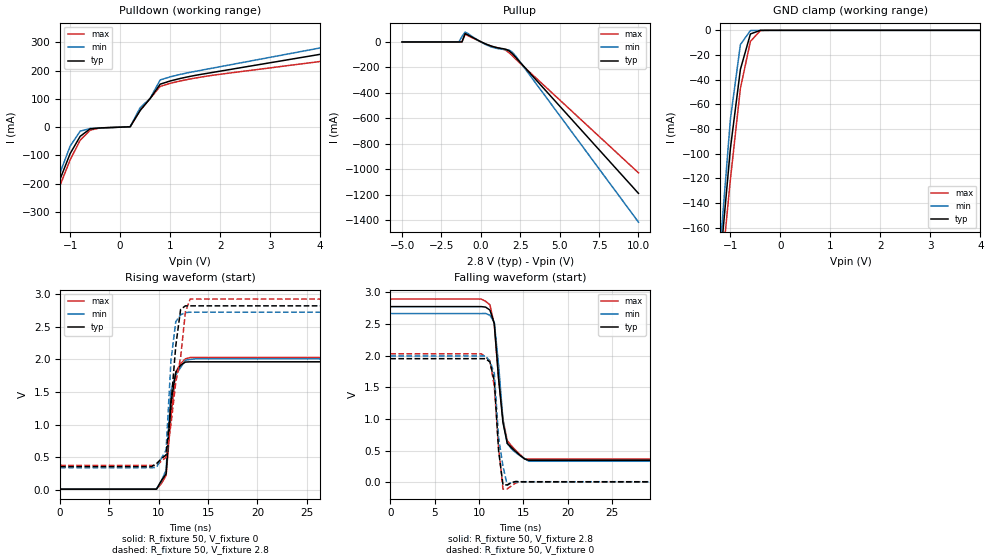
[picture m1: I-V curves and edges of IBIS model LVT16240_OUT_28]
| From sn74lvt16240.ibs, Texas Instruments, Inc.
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|  Model  LVT16240 OUTPUT_28
[Model]   LVT16240_OUT_28
Model_type  3-state
Polarity   Inverting
Enable   Active-Low
Vmeas = 1.5V
Cref = 50pF
Rref = 500
Vref = 0
| variable   typ   min   max
C_comp   9pf   NA   NA
[Temperature Range]   40   -25   100
| Ambient temperature   25   -40   85
[Voltage range]   2.8   2.7   2.9
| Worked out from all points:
|   slope of the pulldown table from 0 to 0.42 V, typ, clamps not added: 6.58 ohm
|   slope of the pullup table from 0 to 0.42 V, typ, clamps not added: 18.2 ohm
|   GND clamp passes 1 mA (typ) near -0.47 V on its own axis
|   rising waveform, R_fixture 50, V_fixture 0: 20-80 % time 667ps typ, 632ps min, 745ps max; typ from 0.01 V to 1.96 V
|   falling waveform, R_fixture 50, V_fixture 2.8: 20-80 % time 1.02ns typ, 979ps min, 1.09ns max; typ from 2.78 V to 0.35 V
|   rising waveform, R_fixture 50, V_fixture 2.8: 20-80 % time 885ps typ, 636ps min, 1.36ns max; typ from 0.357 V to 2.82 V
|   falling waveform, R_fixture 50, V_fixture 0: 20-80 % time 561ps typ, 752ps min, 722ps max; typ from 1.96 V to 0.011 V
[Pullup]
|   Voltage   I(typ)   I(min)   I(max)
-5V       71.69uA    70.79uA    72.81uA
-1.4V     59.65uA    56.79uA    62.02uA
-1.2V     58.5uA     42.93mA    61.73uA
-1V       66.29mA    77.41mA    61.13mA
400mV     -20.47mA   -26.01mA   -21.1mA
800mV     -37.57mA   -44.2mA    -37.86mA
1.4V      -52.85mA   -57.94mA   -55.61mA
1.8V      -71.12mA   -64.42mA   -85.82mA
2V        -92.62mA   -80.77mA   -108.8mA
2.2V      -119.4mA   -109.4mA   -133.2mA
10V       -1.188A    -1.414A    -1.027A
[Pulldown]
|   Voltage   I(typ)   I(min)   I(max)
-5V       -1.962A    -2.061A    -1.913A
-1.6V     -370.6mA   -361.1mA   -385.5mA
-1.4V     -277mA     -261.1mA   -295.6mA
-1V       -93.68mA   -67.2mA    -115.8mA
-800mV    -32.6mA    -14.25mA   -46.39mA
-600mV    -5.937mA   -4.783mA   -10.81mA
200mV     1.287mA    1.519mA    1.262mA
800mV     152.2mA    167.2mA    144.4mA
1V        163.5mA    178.1mA    155.2mA
6.2V      323.5mA    353.6mA    282.3mA
7.4V      359.3mA    393.5mA    309.5mA
10V       436.8mA    479.8mA    368.2mA
[GND Clamp]
|   Voltage   I(typ)   I(min)   I(max)
-5V       -1.902A    -2.118A    -1.805A
-1.2V     -186.1mA   -174.3mA   -205mA
-1V       -95.77mA   -72.03mA   -120.8mA
-800mV    -31.63mA   -11.56mA   -47mA
-600mV    -2.954mA   -182.4uA   -8.963mA
-400mV    -9.622uA   -44.3nA    -176.5uA
5V        29.12nA    43.77nA    45.59nA
[Ramp]
| variable   typ   min   max
dV/dt_r   1.194E-00/6.480E-10  1.182E-00/5.640E-10  1.224E-00/7.370E-10
dV/dt_f   1.452E+00/4.200E-10  1.398E+00/3.890E-10  1.506E+00/5.280E-10
[Rising Waveform]
R_fixture = 50
V_fixture = 0
V_fixture_min = 0
V_fixture_max = 0
C_fixture = 0
L_fixture = 0
|   Time   V(typ)   V(min)   V(max)
0s        10.06mV    10.66mV    10.15mV
9.766ns   10.07mV    12.89mV    10.85mV
10.25ns   138.9mV    131.9mV    93.08mV
10.74ns   244.7mV    304.9mV    219.4mV
11.23ns   1.345V     1.518V     1.118V
11.72ns   1.798V     1.762V     1.807V
12.21ns   1.913V     1.878V     1.938V
12.7ns    1.96V      1.99V      2.01V
13.18ns   1.964V     2V         2.03V
49.71ns   1.964V     2.01V      2.03V
[Falling Waveform]
R_fixture = 50
V_fixture = 2.8
V_fixture_min = 2.7
V_fixture_max = 2.9
C_fixture = 0pf
L_fixture = 0nH
|   Time   V(typ)   V(min)   V(max)
0s        2.777V     2.667V     2.896V
10.25ns   2.777V     2.667V     2.896V
11.23ns   2.722V     2.64V      2.805V
11.72ns   2.509V     2.527V     2.489V
12.21ns   1.638V     1.85V      1.628V
12.7ns    943mV      982.2mV    993.1mV
13.18ns   620.4mV    613.7mV    661.5mV
15.14ns   372.5mV    374.6mV    370.2mV
15.63ns   350.1mV    335.1mV    370.8mV
49.71ns   350.1mV    335.1mV    370.8mV
[Rising Waveform]
R_fixture = 50
V_fixture = 2.8
V_fixture_min = 2.7
V_fixture_max = 2.9
C_fixture = 0pf
L_fixture = 0nH
|   Time   V(typ)   V(min)   V(max)
0s        357mV      339.9mV    375.5mV
9.277ns   357mV      338.8mV    375.5mV
9.766ns   401.4mV    344.5mV    370.4mV
10.74ns   537.6mV    608.4mV    500.8mV
11.23ns   1.297V     1.977V     998.1mV
11.72ns   2.208V     2.581V     1.65V
12.21ns   2.768V     2.685V     2.03V
12.7ns    2.823V     2.719V     2.733V
13.18ns   2.823V     2.726V     2.927V
49.71ns   2.823V     2.726V     2.927V
[Falling Waveform]
R_fixture = 50
V_fixture = 0
V_fixture_min = 0
V_fixture_max = 0
C_fixture = 0pf
L_fixture = 0nH
|   Time   V(typ)   V(min)   V(max)
0s        1.955V     1.998V     2.032V
10.25ns   1.955V     1.998V     2.032V
10.74ns   1.955V     1.998V     1.98V
11.23ns   1.902V     1.912V     1.921V
11.72ns   1.606V     1.724V     1.521V
12.21ns   495.5mV    707.1mV    550.5mV
12.7ns    -36.58mV   252.8mV    -105.7mV
13.18ns   -38.42mV   -42.8mV    -101mV
14.65ns   10.73mV    11.68mV    11.57mV
49.71ns   10.73mV    11.67mV    11.57mV
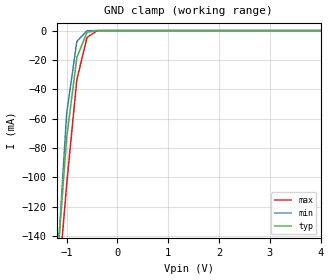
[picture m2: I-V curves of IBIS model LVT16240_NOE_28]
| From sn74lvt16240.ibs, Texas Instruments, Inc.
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|   LVT16240 Input_NOE_28
[Model]   LVT16240_NOE_28
Model_type  Input
Polarity   Inverting
Vinl = 0.8V
Vinh = 2.0V
| variable   typ   min   max
C_comp   4pf   NA   NA
[Temperature Range]   40   -25   100
| Ambient temperature   25   -40   85
[Voltage range]   2.8   2.7   2.9
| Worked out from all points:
|   GND clamp passes 1 mA (typ) near -0.58 V on its own axis
[GND Clamp]
|   Voltage   I(typ)   I(min)   I(max)
-5V       -2.028A    -2.573A    -1.762A
-1.2V     -164.9mA   -168.7mA   -187.5mA
-1V       -72.94mA   -56.27mA   -104.7mA
-800mV    -18.37mA   -7.379mA   -33.44mA
-600mV    -1.13mA    -93.14uA   -4.688mA
-400mV    -1.845uA   -78.68nA   -66.71uA
5V        1.98nA     79.5nA     382.9pA
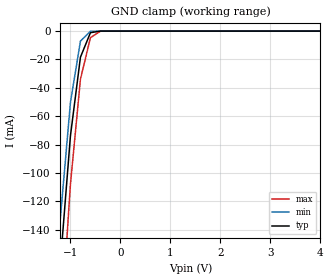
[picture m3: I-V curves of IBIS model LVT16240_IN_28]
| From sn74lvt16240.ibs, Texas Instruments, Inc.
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|   LVT16240 Input_IN_28
[Model]   LVT16240_IN_28
Model_type  Input
Polarity   Inverting
Vinl = 0.8V
Vinh = 2.0V
| variable   typ   min   max
C_comp   4pf   NA   NA
[Temperature Range]   40   -25   100
| Ambient temperature   25   -40   85
[Voltage range]   2.8   2.7   2.9
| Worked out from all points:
|   GND clamp passes 1 mA (typ) near -0.58 V on its own axis
[GND Clamp]
|   Voltage   I(typ)   I(min)   I(max)
-5V       -1.85A     -1.667A    -2.272A
-1.4V     -251.5mA   -212mA     -324.3mA
-1.2V     -162.7mA   -131.2mA   -216.1mA
-1V       -73.83mA   -50.34mA   -107.9mA
-800mV    -18.39mA   -7.035mA   -33.93mA
-600mV    -1.126mA   -89.99uA   -4.642mA
-400mV    -1.9uA     -23.21nA   -62.86uA
5V        233.8pA    6.711nA    2.669nA
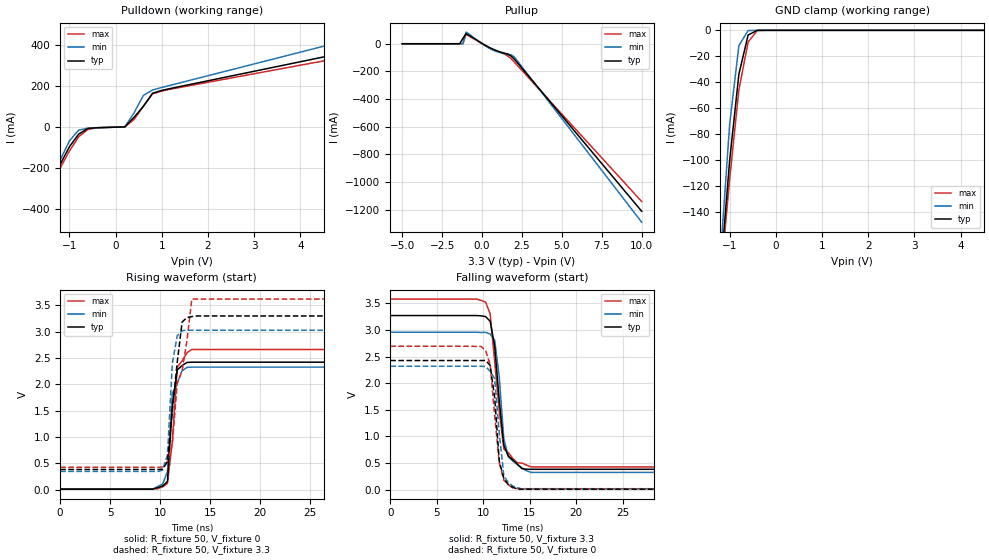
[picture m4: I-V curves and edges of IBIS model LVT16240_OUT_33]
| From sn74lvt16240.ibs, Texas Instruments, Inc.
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|  Model  LVT16240 OUTPUT_33
[Model]   LVT16240_OUT_33
Model_type  3-state
Polarity   Inverting
Enable   Active-Low
Vmeas = 1.5V
Cref = 50pF
Rref = 500
Vref = 0
| variable   typ   min   max
C_comp   9pf   NA   NA
[Temperature Range]   40   -25   100
| Ambient temperature   25   -40   85
[Voltage range]   3.3   3.0   3.6
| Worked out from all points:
|   slope of the pulldown table from 0 to 0.495 V, typ, clamps not added: 6.73 ohm
|   slope of the pullup table from 0 to 0.495 V, typ, clamps not added: 15.6 ohm
|   GND clamp passes 1 mA (typ) near -0.46 V on its own axis
|   rising waveform, R_fixture 50, V_fixture 0: 20-80 % time 627ps typ, 530ps min, 650ps max; typ from 0.013 V to 2.42 V
|   falling waveform, R_fixture 50, V_fixture 3.3: 20-80 % time 906ps typ, 867ps min, 1.08ns max; typ from 3.27 V to 0.384 V
|   rising waveform, R_fixture 50, V_fixture 3.3: 20-80 % time 946ps typ, 513ps min, 1.47ns max; typ from 0.386 V to 3.3 V
|   falling waveform, R_fixture 50, V_fixture 0: 20-80 % time 728ps typ, 743ps min, 853ps max; typ from 2.43 V to 0.01 V
[Pullup]
|  Voltage   I(typ)   I(min)   I(max)
-5V       85.74uA    80.58uA    92.35uA
-1.4V     74uA       65.9uA     82.45uA
-1.2V     38.29mA    64.76uA    82.13uA
-1V       73.56mA    84.38mA    70.19mA
0V        2.843mA    96.35uA    -10.33uA
600mV     -34.83mA   -41.49mA   -37.21mA
1V        -54.04mA   -59.83mA   -57.18mA
1.6V      -74.55mA   -74.88mA   -86.68mA
1.8V      -87.5mA    -79.01mA   -106.4mA
2V        -109.1mA   -93.81mA   -129.9mA
10V       -1.212A    -1.291A    -1.141A
[Pulldown]
|   Voltage   I(typ)   I(min)   I(max)
-5V       -1.818A    -2.047A    -1.651A
-2V       -526.5mA   -557.8mA   -505.4mA
-1.8V     -440.4mA   -458.5mA   -429mA
-1V       -95.95mA   -67.29mA   -116.7mA
-800mV    -34.25mA   -14.46mA   -46.92mA
-600mV    -6.43mA    -4.873mA   -11.08mA
200mV     1.233mA    1.501mA    1.297mA
600mV     101.2mA    154.1mA    101.2mA
800mV     165.3mA    181mA      162.1mA
6.2V      420.9mA    491.8mA    393.5mA
7.8V      495.1mA    583.7mA    460mA
10V       597.2mA    710mA      551.6mA
[GND Clamp]
|   Voltage   I(typ)   I(min)   I(max)
-5V       -1.854A    -2.119A    -1.677A
-1.2V     -188mA     -174.8mA   -192.8mA
-1V       -100.4mA   -72.44mA   -114.8mA
-800mV    -33.78mA   -11.76mA   -45.84mA
-600mV    -3.592mA   -186.8uA   -9.032mA
-400mV    -14.67uA   -44.44nA   -181.3uA
5V        4.157nA    25.36nA    17.36nA
[Ramp]
| variable   typ   min   max
dV/dt_r   1.482E+00/4.900E-10  1.362E+00/4.000E-10  1.578E+00/5.380E-10
dV/dt_f   1.728E+00/4.230E-10  1.560E+00/3.900E-10  1.884E+00/4.980E-10
[Rising Waveform]
R_fixture = 50
V_fixture = 0
V_fixture_min = 0
V_fixture_max = 0
C_fixture = 0
L_fixture = 0
|   Time   V(typ)   V(min)   V(max)
0s        12.64mV    12.94mV    20.38mV
9.277ns   12.64mV    12.94mV    20.38mV
10.25ns   71.66mV    108mV      55.58mV
10.74ns   158.2mV    344.5mV    122.8mV
11.23ns   1.583V     1.834V     917.5mV
11.72ns   2.276V     2.021V     2.33V
12.21ns   2.359V     2.26V      2.449V
12.7ns    2.418V     2.324V     2.604V
13.18ns   2.423V     2.329V     2.664V
49.71ns   2.423V     2.329V     2.664V
[Falling Waveform]
R_fixture = 50
V_fixture = 3.3
V_fixture_min = 3
V_fixture_max = 3.6
C_fixture = 0pf
L_fixture = 0nH
|   Time   V(typ)   V(min)   V(max)
0s        3.272V     2.959V     3.582V
10.25ns   3.252V     2.956V     3.525V
10.74ns   3.166V     2.925V     3.303V
11.23ns   2.696V     2.808V     2.403V
11.72ns   1.674V     2.115V     1.478V
12.21ns   837.1mV    957.4mV    766.5mV
12.7ns    627.9mV    620.3mV    696.3mV
13.67ns   480.2mV    470.7mV    504.9mV
15.14ns   383.6mV    325.6mV    428.1mV
49.71ns   383.6mV    325.6mV    428.1mV
[Rising Waveform]
R_fixture = 50
V_fixture = 3.3
V_fixture_min = 3
V_fixture_max = 3.6
C_fixture = 0pf
L_fixture = 0nH
|   Time   V(typ)   V(min)   V(max)
0s        386.3mV    349.2mV    427.7mV
9.766ns   386.3mV    349.2mV    427.7mV
10.25ns   391.8mV    375.5mV    434.8mV
10.74ns   529.8mV    662.7mV    539.9mV
11.23ns   1.498V     2.403V     877.9mV
11.72ns   2.425V     2.924V     2.027V
12.21ns   3.186V     3.022V     2.259V
12.7ns    3.27V      3.03V      2.845V
13.18ns   3.289V     3.03V      3.621V
49.71ns   3.3V       3.03V      3.621V
[Falling Waveform]
R_fixture = 50
V_fixture = 0
V_fixture_min = 0
V_fixture_max = 0
C_fixture = 0pf
L_fixture = 0nH
|   Time   V(typ)   V(min)   V(max)
0s        2.427V     2.32V      2.695V
9.766ns   2.427V     2.318V     2.692V
10.25ns   2.428V     2.316V     2.617V
10.74ns   2.336V     2.225V     2.351V
11.23ns   1.726V     2.086V     1.389V
11.72ns   534.5mV    1.062V     500mV
12.21ns   214.7mV    265.5mV    178.6mV
13.18ns   45.46mV    69.1mV     31.28mV
14.16ns   10.14mV    12.09mV    18.79mV
49.71ns   10.14mV    12.09mV    18.79mV
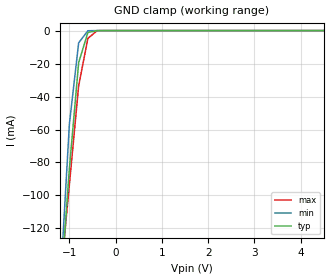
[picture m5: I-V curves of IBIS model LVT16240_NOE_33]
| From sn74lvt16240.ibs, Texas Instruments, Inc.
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|   LVT16240 Input NOE_33
[Model]   LVT16240_NOE_33
Model_type  Input
Polarity   Inverting
Vinl = 0.8V
Vinh = 2.0V
| variable   typ   min   max
C_comp   4pf   NA   NA
[Temperature Range]   40   -25   100
| Ambient temperature   25   -40   85
[Voltage range]   3.3   3.0   3.6
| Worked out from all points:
|   GND clamp passes 1 mA (typ) near -0.57 V on its own axis
[GND Clamp]
|   Voltage   I(typ)   I(min)   I(max)
-5V       -1.639A    -2.027A    -1.288A
-1.2V     -161.4mA   -155.2mA   -153mA
-1V       -83.58mA   -56.61mA   -93.26mA
-800mV    -19.45mA   -7.441mA   -33.54mA
-600mV    -1.145mA   -95.18uA   -4.704mA
-400mV    -1.838uA   -62.07nA   -66.87uA
5V        368pA      73.94nA    531.1pA
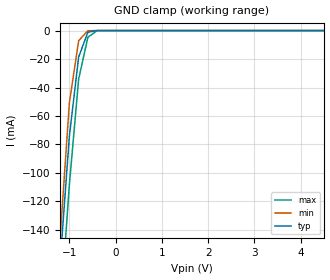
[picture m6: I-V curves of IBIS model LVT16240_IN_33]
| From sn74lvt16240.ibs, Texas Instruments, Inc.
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|   LVT16240 Input_IN
[Model]   LVT16240_IN_33
Model_type  Input
Polarity   Inverting
Vinl = 0.8V
Vinh = 2.0V
| variable   typ   min   max
C_comp   4pf   NA   NA
[Temperature Range]   40   -25   100
| Ambient temperature   25   -40   85
[Voltage range]   3.3   3.0   3.6
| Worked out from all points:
|   GND clamp passes 1 mA (typ) near -0.57 V on its own axis
[GND Clamp]
|   Voltage   I(typ)   I(min)   I(max)
-5V       -1.849A    -2.201A    -1.634A
-1.2V     -162.7mA   -145.2mA   -199.9mA
-1V       -73.98mA   -50.6mA    -108mA
-800mV    -18.53mA   -7.104mA   -34.05mA
-600mV    -1.146mA   -92.29uA   -4.667mA
-400mV    -1.969uA   -24.86nA   -63.77uA
5V        507.9pA    6.884nA    375.3pA
